VERSION 5.7 ;
  NOWIREEXTENSIONATPIN ON ;
  DIVIDERCHAR "/" ;
  BUSBITCHARS "[]" ;
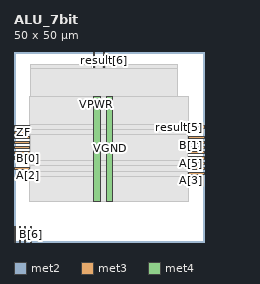
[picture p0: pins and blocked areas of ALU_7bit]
MACRO ALU_7bit
  CLASS BLOCK ;
  FOREIGN ALU_7bit ;
  ORIGIN 0.000 0.000 ;
  SIZE 50.000 BY 50.000 ;
  PIN A[0]
    DIRECTION INPUT ;
    USE SIGNAL ;
    ANTENNAGATEAREA 0.196500 ;
    PORT
      LAYER met2 ;
        RECT 20.790 46.000 21.070 50.000 ;
    END
  END A[0]
  PIN A[1]
    DIRECTION INPUT ;
    USE SIGNAL ;
    ANTENNAGATEAREA 0.196500 ;
    PORT
      LAYER met3 ;
        RECT 0.000 27.240 4.000 27.840 ;
    END
  END A[1]
  PIN A[2]
    DIRECTION INPUT ;
    USE SIGNAL ;
    ANTENNAGATEAREA 0.196500 ;
    PORT
      LAYER met3 ;
        RECT 0.000 19.080 4.000 19.680 ;
    END
  END A[2]
  PIN A[3]
    DIRECTION INPUT ;
    USE SIGNAL ;
    ANTENNAGATEAREA 0.196500 ;
    PORT
      LAYER met3 ;
        RECT 46.000 17.720 50.000 18.320 ;
    END
  END A[3]
  PIN A[4]
    DIRECTION INPUT ;
    USE SIGNAL ;
    ANTENNAGATEAREA 0.196500 ;
    PORT
      LAYER met3 ;
        RECT 46.000 19.080 50.000 19.680 ;
    END
  END A[4]
  PIN A[5]
    DIRECTION INPUT ;
    USE SIGNAL ;
    ANTENNAGATEAREA 0.213000 ;
    PORT
      LAYER met3 ;
        RECT 46.000 20.440 50.000 21.040 ;
    END
  END A[5]
  PIN A[6]
    DIRECTION INPUT ;
    USE SIGNAL ;
    ANTENNAGATEAREA 0.213000 ;
    PORT
      LAYER met3 ;
        RECT 46.000 21.800 50.000 22.400 ;
    END
  END A[6]
  PIN B[0]
    DIRECTION INPUT ;
    USE SIGNAL ;
    ANTENNAGATEAREA 0.196500 ;
    PORT
      LAYER met3 ;
        RECT 0.000 21.800 4.000 22.400 ;
    END
  END B[0]
  PIN B[1]
    DIRECTION INPUT ;
    USE SIGNAL ;
    ANTENNAGATEAREA 0.213000 ;
    PORT
      LAYER met3 ;
        RECT 46.000 23.160 50.000 23.760 ;
    END
  END B[1]
  PIN B[2]
    DIRECTION INPUT ;
    USE SIGNAL ;
    ANTENNAGATEAREA 0.213000 ;
    PORT
      LAYER met3 ;
        RECT 0.000 24.520 4.000 25.120 ;
    END
  END B[2]
  PIN B[3]
    DIRECTION INPUT ;
    USE SIGNAL ;
    PORT
      LAYER met2 ;
        RECT 0.090 0.000 0.370 4.000 ;
    END
  END B[3]
  PIN B[4]
    DIRECTION INPUT ;
    USE SIGNAL ;
    PORT
      LAYER met2 ;
        RECT 1.470 0.000 1.750 4.000 ;
    END
  END B[4]
  PIN B[5]
    DIRECTION INPUT ;
    USE SIGNAL ;
    PORT
      LAYER met2 ;
        RECT 2.850 0.000 3.130 4.000 ;
    END
  END B[5]
  PIN B[6]
    DIRECTION INPUT ;
    USE SIGNAL ;
    PORT
      LAYER met2 ;
        RECT 4.230 0.000 4.510 4.000 ;
    END
  END B[6]
  PIN OP
    DIRECTION INPUT ;
    USE SIGNAL ;
    ANTENNAGATEAREA 0.196500 ;
    PORT
      LAYER met3 ;
        RECT 46.000 24.520 50.000 25.120 ;
    END
  END OP
  PIN VGND
    DIRECTION INOUT ;
    USE GROUND ;
    PORT
      LAYER met4 ;
        RECT 24.340 10.640 25.940 38.320 ;
    END
  END VGND
  PIN VPWR
    DIRECTION INOUT ;
    USE POWER ;
    PORT
      LAYER met4 ;
        RECT 21.040 10.640 22.640 38.320 ;
    END
  END VPWR
  PIN ZF
    DIRECTION OUTPUT ;
    USE SIGNAL ;
    ANTENNADIFFAREA 0.445500 ;
    PORT
      LAYER met3 ;
        RECT 0.000 28.600 4.000 29.200 ;
    END
  END ZF
  PIN result[0]
    DIRECTION OUTPUT ;
    USE SIGNAL ;
    ANTENNADIFFAREA 0.445500 ;
    PORT
      LAYER met3 ;
        RECT 0.000 29.960 4.000 30.560 ;
    END
  END result[0]
  PIN result[1]
    DIRECTION OUTPUT ;
    USE SIGNAL ;
    ANTENNADIFFAREA 0.445500 ;
    PORT
      LAYER met3 ;
        RECT 0.000 25.880 4.000 26.480 ;
    END
  END result[1]
  PIN result[2]
    DIRECTION OUTPUT ;
    USE SIGNAL ;
    ANTENNADIFFAREA 0.445500 ;
    PORT
      LAYER met3 ;
        RECT 0.000 23.160 4.000 23.760 ;
    END
  END result[2]
  PIN result[3]
    DIRECTION OUTPUT ;
    USE SIGNAL ;
    ANTENNADIFFAREA 0.445500 ;
    PORT
      LAYER met3 ;
        RECT 46.000 25.880 50.000 26.480 ;
    END
  END result[3]
  PIN result[4]
    DIRECTION OUTPUT ;
    USE SIGNAL ;
    ANTENNADIFFAREA 0.445500 ;
    PORT
      LAYER met3 ;
        RECT 46.000 27.240 50.000 27.840 ;
    END
  END result[4]
  PIN result[5]
    DIRECTION OUTPUT ;
    USE SIGNAL ;
    ANTENNADIFFAREA 0.445500 ;
    PORT
      LAYER met3 ;
        RECT 46.000 29.960 50.000 30.560 ;
    END
  END result[5]
  PIN result[6]
    DIRECTION OUTPUT ;
    USE SIGNAL ;
    ANTENNADIFFAREA 0.445500 ;
    PORT
      LAYER met2 ;
        RECT 23.550 46.000 23.830 50.000 ;
    END
  END result[6]
  OBS
      LAYER nwell ;
        RECT 5.330 10.795 44.350 38.165 ;
      LAYER li1 ;
        RECT 5.520 10.795 44.160 38.165 ;
      LAYER met1 ;
        RECT 4.210 10.640 44.160 38.320 ;
      LAYER met2 ;
        RECT 4.230 45.720 20.510 46.650 ;
        RECT 21.350 45.720 23.270 46.650 ;
        RECT 24.110 45.720 43.140 46.650 ;
        RECT 4.230 10.695 43.140 45.720 ;
      LAYER met3 ;
        RECT 3.990 30.960 46.000 38.245 ;
        RECT 4.400 29.560 45.600 30.960 ;
        RECT 4.400 28.240 46.000 29.560 ;
        RECT 4.400 21.400 45.600 28.240 ;
        RECT 3.990 20.080 45.600 21.400 ;
        RECT 4.400 18.680 45.600 20.080 ;
        RECT 3.990 17.320 45.600 18.680 ;
        RECT 3.990 10.715 46.000 17.320 ;
  END
END ALU_7bit
END LIBRARY

